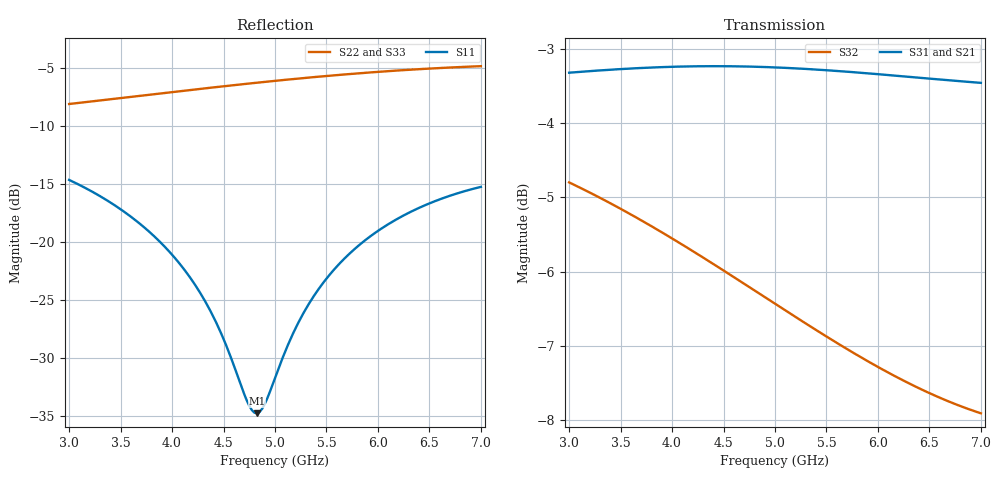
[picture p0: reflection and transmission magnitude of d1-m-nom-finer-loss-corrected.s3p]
! yapnr Order 0 prediction d1-m-nom-finer: predictions/D1/variants/d1-star-m-nom/finer.s3p, loss-corrected
! substrate M-nom; coupon model OSHPARK-4L-FR408HR; correction: ratio (port line)
! |S21|, |S31| (and S12, S13) scaled, phases kept; 50 ohm, e^(+jwt)
# GHz S RI R 50
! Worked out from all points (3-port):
!   161 points, 3 GHz to 7 GHz, reference 50 ohm
!   strongest paths, dB at 3 GHz, 4 GHz, 5 GHz, 6 GHz, 7 GHz:
!     S31: -3.3, -3.2, -3.2, -3.3, -3.5
!     S21: -3.3, -3.2, -3.2, -3.3, -3.5
!     S32: -4.8, -5.6, -6.4, -7.3, -7.9
!   lowest |S11| = -34.7 dB at 4.825 GHz (marker M1), VSWR 1.04, Z = 51.8 - j0.575 ohm
!   |S11| at or under -10 dB: start of sweep to end of sweep
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3  -0.0708 0.172  0.0986 -0.6752  0.0986 -0.6752
   0.0985 -0.6752  0.1433 0.3683  -0.1529 -0.5549
   0.0985 -0.6752  -0.1529 -0.5549  0.1433 0.3683
3.6  -0.013 0.1285  -0.1037 -0.679  -0.1037 -0.679
     -0.1038 -0.6789  0.2759 0.322  -0.318 -0.4458
     -0.1038 -0.6789  -0.318 -0.4458  0.2759 0.322
4.075  0.015 0.0795  -0.2611 -0.6375  -0.2611 -0.6375
       -0.2611 -0.6374  0.3689 0.2553  -0.4069 -0.3299
       -0.2611 -0.6374  -0.4069 -0.3299  0.3689 0.2553
4.375  0.0223 0.0452  -0.3539 -0.5916  -0.3539 -0.5916
       -0.3539 -0.5915  0.4189 0.2007  -0.4425 -0.2504
       -0.3539 -0.5915  -0.4425 -0.2504  0.4189 0.2007
4.825  0.0175 -0.00555  -0.477 -0.4968  -0.477 -0.4968
       -0.4769 -0.4967  0.4771 0.1037  -0.4676 -0.1306
       -0.4769 -0.4967  -0.4676 -0.1306  0.4771 0.1037
5  0.0107 -0.0238  -0.5182 -0.4526  -0.5182 -0.4526
   -0.5181 -0.4525  0.4934 0.062  -0.4691 -0.0855
   -0.5181 -0.4525  -0.4691 -0.0855  0.4934 0.062
5.325  -0.00854 -0.0533  -0.5832 -0.3617  -0.5832 -0.3617
       -0.5831 -0.3616  0.5131 -0.0196  -0.4611 -0.00593
       -0.5831 -0.3616  -0.4611 -0.00593  0.5131 -0.0196
5.725  -0.0414 -0.0794  -0.6405 -0.2378  -0.6405 -0.2378
       -0.6405 -0.2378  0.5174 -0.124  -0.4356 0.0823
       -0.6405 -0.2378  -0.4356 0.0823  0.5174 -0.124
6.3  -0.0979 -0.0919  -0.6764 -0.0479  -0.6764 -0.0479
     -0.6763 -0.0478  0.484 -0.2714  -0.3773 0.1877
     -0.6763 -0.0478  -0.3773 0.1877  0.484 -0.2714
7  -0.161 -0.0649  -0.647 0.1808  -0.647 0.1808
   -0.6468 0.1809  0.3866 -0.426  -0.2857 0.2831
   -0.6468 0.1809  -0.2857 0.2831  0.3866 -0.426
